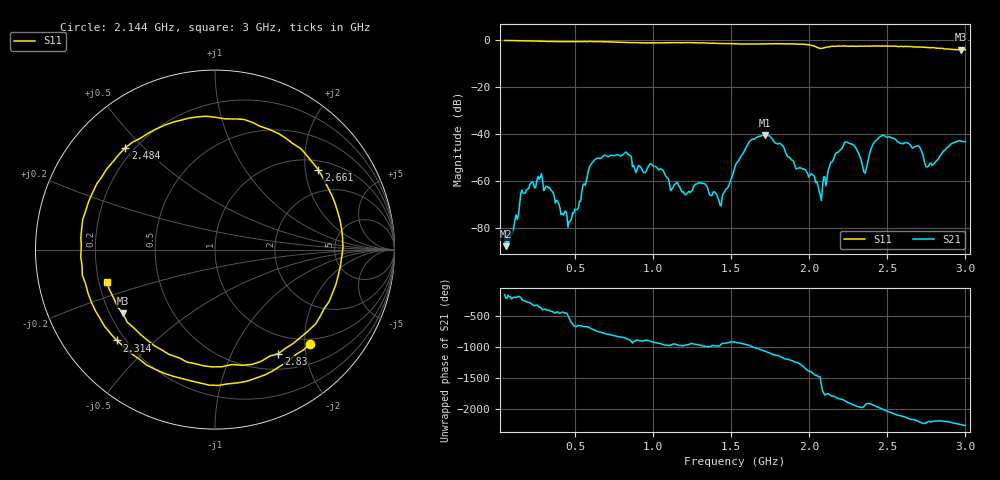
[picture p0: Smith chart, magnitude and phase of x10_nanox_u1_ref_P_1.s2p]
! nanovna_capture.py 2026-10-18T20:54:56+0900
! NanoVNA-F_V2 fw 0.6.0 SN 4A3639384505514B
! cal: load open short thru cal'ed  over 50000000-3000000000 Hz, 201 points
! points 401, avg 4
! S21: green ~10 mm loop -> GSM antenna; genuine Nano X u1 at position P (user-found 'perfect placement', description TBD), placement 1
# HZ S RI R 50
! S12 and S22 are not measured (written as 0)
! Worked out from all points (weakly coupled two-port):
!   401 points, 50 MHz to 3 GHz, reference 50 ohm
!   highest |S21| = -40.42 dB at 1.717 GHz (marker M1); lowest = -87.7 dB at 57.38 MHz (marker M2)
!   lowest |S11| = -4.1 dB at 2.97 GHz (marker M3), VSWR 4.32, Z = 12.6 - j14.6 ohm
!   |S11| at or under -10 dB: nowhere
!   S12 and S22 are empty: the file has one direction only
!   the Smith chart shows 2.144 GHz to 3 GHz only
!   S11 on the Smith chart (normalised r, x): 2.144 GHz: 0.90, -2.12; 2.314 GHz: 0.17, -0.38; 2.484 GHz: 0.17, +0.44; 2.661 GHz: 1.25, +2.36; 2.83 GHz: 0.71, -1.54; 3 GHz: 0.23, -0.14
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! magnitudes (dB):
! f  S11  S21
! 50 MHz  -0.1  -82.7
! 57.38 MHz  -0.1  -87.7
! 271.2 MHz  -0.4  -59.2
! 463 MHz  -0.6  -77.4
! 544.1 MHz  -0.6  -64.6
! 684.2 MHz  -0.6  -49.2
! 1.038 GHz  -1.1  -55.2
! 1.429 GHz  -1.4  -70.1
! 1.525 GHz  -1.5  -54.0
! 1.717 GHz  -1.6  -40.4
! 2.019 GHz  -2.2  -57.2
! 2.071 GHz  -3.5  -65.8
! 2.144 GHz  -2.6  -52.1
! 2.24 GHz  -2.5  -43.4
! 2.314 GHz  -2.6  -47.9
! 2.358 GHz  -2.5  -56.6
! 2.484 GHz  -2.4  -40.8
! 2.513 GHz  -2.5  -41.1
! 2.661 GHz  -2.8  -45.9
! 2.83 GHz  -3.4  -50.2
! 2.97 GHz  -4.1  -42.9
! 3 GHz  -4.1  -43.2
